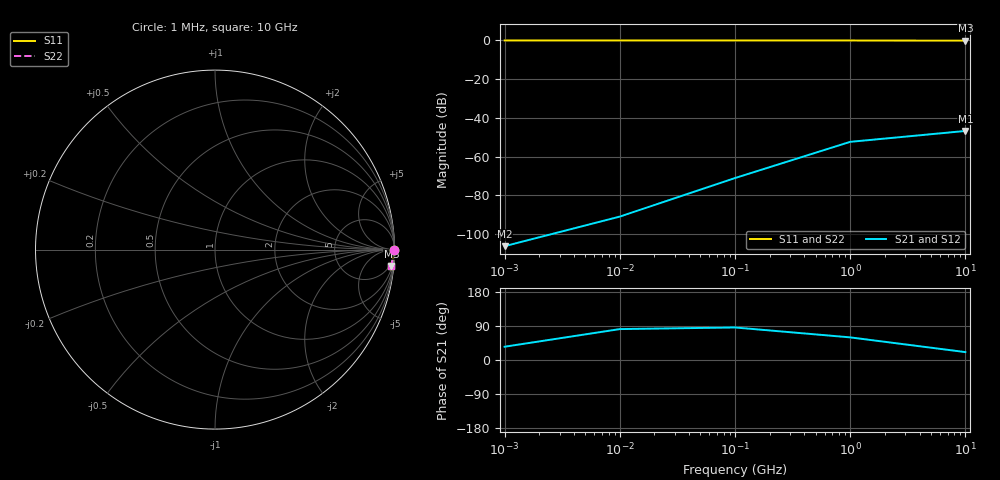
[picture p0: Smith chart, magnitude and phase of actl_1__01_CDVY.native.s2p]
! Sonnet Data File
! From: em Version : 18.53-Lite
! From Project: actl_1__01_CDVY
! Data is NOT De-embedded
! Data File Written: 10/12/2026 12:07:03
!< HDATE 10/12/2026 12:07:03
!< MDATE 10/12/2026 12:07:03
# GHZ S RI R 50.00000
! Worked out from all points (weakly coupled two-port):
!   5 points, 1 MHz to 10 GHz, reference 50 ohm
!   highest |S21| = -46.73 dB at 10 GHz (marker M1); lowest = -106.2 dB at 1 MHz (marker M2)
!   lowest |S11| = -0.1 dB at 10 GHz (marker M3), VSWR 147.25, Z = 157 - j1.06e+03 ohm
!   |S11| at or under -10 dB: nowhere
!   |S22| runs from -0.1 to 0.0 dB; largest |S21 - S12| = 2.8e-11
0.001  1 -1.42e-05  4e-06 2.8e-06  4e-06 2.8e-06  1 -1.42e-05
0.01  1 -0.000142  4.16e-06 2.8e-05  4.16e-06 2.8e-05  1 -0.000142
0.1  1 -0.00142  2.03e-05 0.000279  2.03e-05 0.000279  1 -0.00142
1  0.9978 -0.0131  0.00122 0.00208  0.00122 0.00208  0.9978 -0.0131
10  0.9823 -0.0907  0.00431 0.00164  0.00431 0.00164  0.9823 -0.0907
